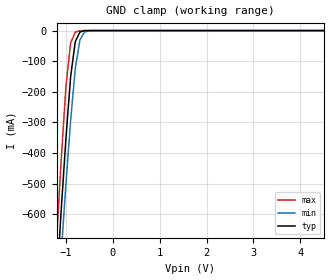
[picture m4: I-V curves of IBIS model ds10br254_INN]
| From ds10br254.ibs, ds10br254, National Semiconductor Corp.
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[Model]   ds10br254_INN
Model_type Input
Polarity Inverting
Vinh=1.25
Vinl=1.15
C_comp   1.7pF   1.7pF   1.7pF
[Model Spec]
S_overshoot_high   3.3   3.0   3.6
S_overshoot_low   0.0   0.0   0.0
[Temperature Range]   25   85   -40
[Voltage Range]   3.3   3.0   3.6
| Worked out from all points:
|   GND clamp passes 1 mA (typ) near -0.62 V on its own axis
[GND Clamp]
|V(groundclamp)   I(typ)   I(min)   I(max)
-3.6V     -7.949A    -7.688A    -8.364A
-1.2V     -837.2mA   -968.2mA   -688.4mA
-1.1V     -586.8mA   -729.1mA   -422.6mA
-1V       -353.4mA   -502.6mA   -183.7mA
-900mV    -151.8mA   -295.7mA   -40.94mA
-800mV    -36.07mA   -124.3mA   -4.991mA
-700mV    -4.641mA   -29.98mA   -506.7uA
-600mV    -299.4uA   -4.1mA     -51.64uA
-500mV    -23.36uA   -273.5uA   -3.241uA
7.2V      407.9pA    9.955nA    116.1pA
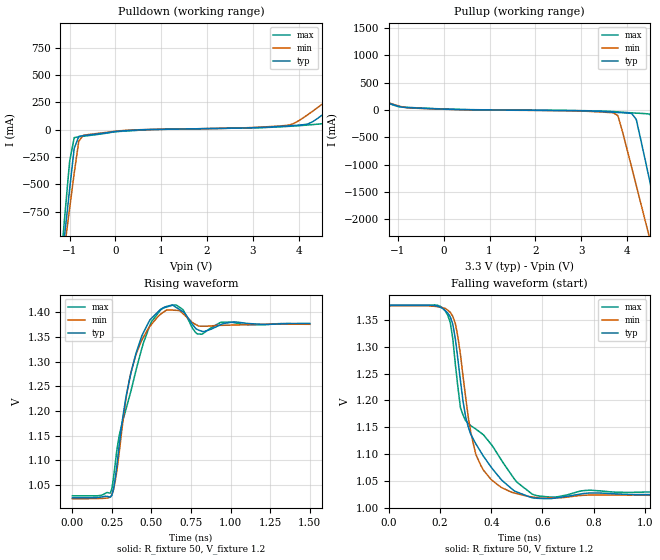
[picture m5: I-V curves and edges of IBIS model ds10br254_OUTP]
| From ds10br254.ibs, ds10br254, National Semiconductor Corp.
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[Model]   ds10br254_OUTP
Model_type Output
Polarity Non-Inverting
Vref=1.2
Vmeas=1.2
Rref=50   | 100 Ohms Across Outputs OUTP and OUTN
Cref=0p
C_comp   1.2pF   1.2pF   1.2pF
[Temperature Range]   25   85   -40
[Voltage Range]   3.3   3.0   3.6
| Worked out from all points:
|   slope of the pulldown table from 0 to 0.495 V, typ, clamps not added: 34.3 ohm
|   slope of the pullup table from 0 to 0.495 V, typ, clamps not added: 47 ohm
|   rising waveform, R_fixture 50, V_fixture 1.2: 20-80 % time 111ps typ, 106ps min, 149ps max; typ from 1.02 V to 1.38 V
|   falling waveform, R_fixture 50, V_fixture 1.2: 20-80 % time 109ps typ, 71.9ps min, 175ps max; typ from 1.38 V to 1.02 V
[Pullup]
|Vtable   I(typ)   I(min)   I(max)
-3.6V     1.45A      1.412A     1.503A
-2.8V     789.4mA    836.2mA    772.6mA
-2.3V     518.9mA    504.5mA    548.4mA
-1V       72.44mA    79.95mA    65.45mA
3.7V      -39.34mA   -49.88mA   -26.54mA
3.8V      -44.24mA   -102.6mA   -33.05mA
4.2V      -170.1mA   -1.377A    -55.31mA
4.5V      -1.319A    -2.371A    -73.35mA
4.6V      -1.708A    -2.703A    -291.1mA
4.7V      -2.099A    -3.035A    -765.9mA
5V        -3.272A    -4.033A    -2.216A
7.2V      -11.89A    -11.35A    -12.92A
[Pulldown]
|V(pulldown)   I(typ)   I(min)   I(max)
-3.6V     -10.73A    -9.367A    -12.93A
-1.2V     -1.319A    -1.379A    -1.246A
-1.1V     -931.4mA   -1.049A    -765mA
-1V       -546.9mA   -721.8mA   -290.3mA
-900mV    -170.4mA   -397.9mA   -72.83mA
-800mV    -61.94mA   -104.3mA   -64.74mA
3.8V      35.78mA    43.78mA    31.11mA
4.6V      163.4mA    262.9mA    64.59mA
5.3V      410.7mA    511.8mA    310.7mA
5.9V      656.1mA    919.5mA    555.9mA
6.4V      1.05A      1.282A     783.4mA
7.2V      1.717A     1.864A     1.521A
[Ramp]
|   typ   min   max
dV/dt_r   212m/125p   212m/139p   208m/155p
dV/dt_f   212m/125p   212m/139p   208m/155p
R_load=50
[Rising Waveform]
R_fixture=50
V_fixture=1.2
V_fixture_min=1.1997
V_fixture_max=1.2026
0s        1.024V     1.023V     1.028V
250ps     1.03V      1.031V     1.043V
300ps     1.141V     1.126V     1.156V
370ps     1.277V     1.278V     1.241V
450ps     1.36V      1.35V      1.339V
560ps     1.407V     1.397V     1.406V
660ps     1.409V     1.404V     1.414V
790ps     1.365V     1.374V     1.356V
940ps     1.376V     1.374V     1.38V
1.5ns     1.378V     1.376V     1.376V
[Falling Waveform]
R_fixture=50
V_fixture=1.2
V_fixture_min=1.1997
V_fixture_max=1.2026
0s        1.377V     1.376V     1.377V
190ps     1.376V     1.375V     1.377V
240ps     1.356V     1.364V     1.346V
260ps     1.315V     1.343V     1.267V
280ps     1.236V     1.285V     1.186V
290ps     1.198V     1.245V     1.173V
340ps     1.119V     1.099V     1.146V
440ps     1.052V     1.038V     1.088V
590ps     1.017V     1.018V     1.021V
1.5ns     1.024V     1.022V     1.029V
